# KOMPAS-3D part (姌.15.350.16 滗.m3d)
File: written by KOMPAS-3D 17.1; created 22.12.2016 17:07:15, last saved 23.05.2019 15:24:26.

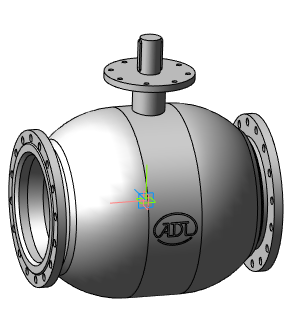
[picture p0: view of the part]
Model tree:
1. Операция без истории:3  (labels: Сталь 20  ГОСТ 1050-88)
